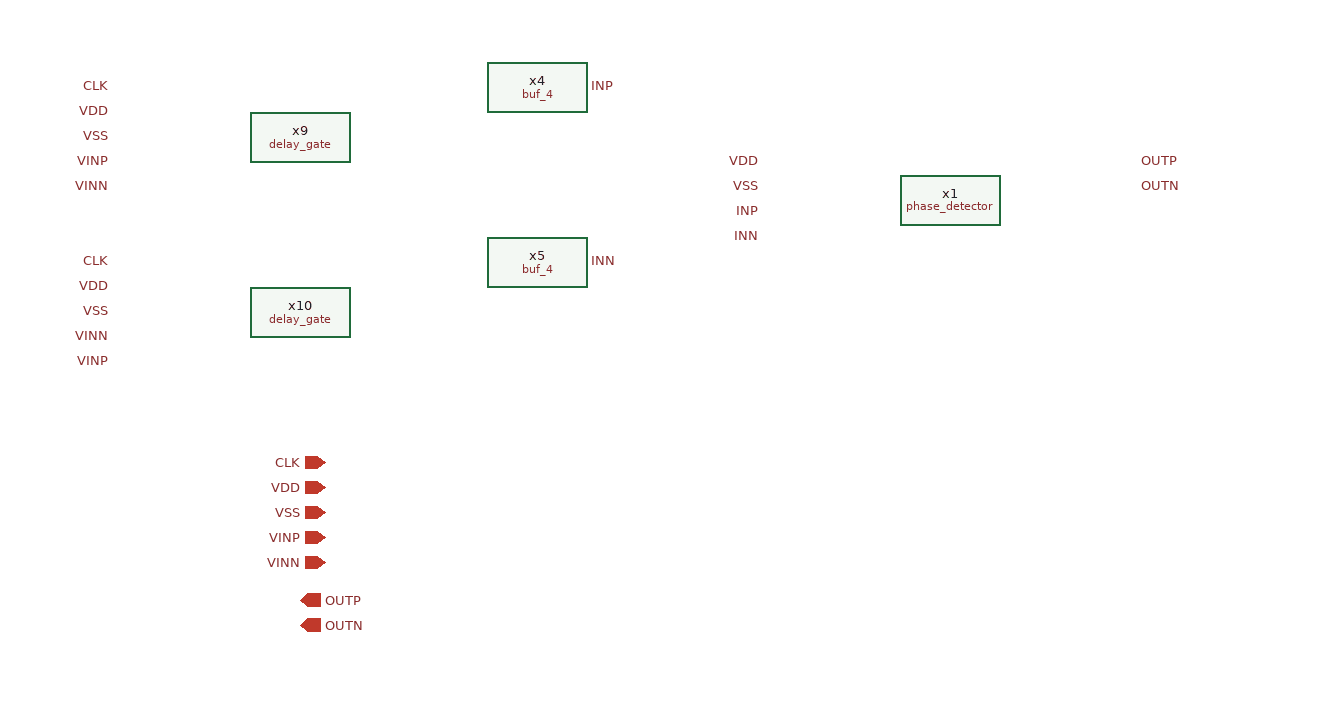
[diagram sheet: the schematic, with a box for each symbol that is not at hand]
v {xschem version=3.4.6 file_version=1.2}
G {}
K {}
V {}
S {}
E {}
C {devices/lab_wire.sym} 1020 -480 0 1 {name=p27 sig_type=std_logic lab=OUTN}
C {devices/lab_wire.sym} 1020 -500 0 1 {name=p28 sig_type=std_logic lab=OUTP}
C {delay_gate.sym} 350 -520 0 0 {name=x9}
C {devices/lab_wire.sym} 580 -560 0 1 {name=p19 sig_type=std_logic lab=INP}
C {delay_gate.sym} 350 -380 0 0 {name=x10}
C {devices/lab_wire.sym} 580 -420 0 1 {name=p20 sig_type=std_logic lab=INN}
C {devices/lab_wire.sym} 200 -540 0 0 {name=p23 sig_type=std_logic lab=VDD}
C {devices/lab_wire.sym} 200 -400 0 0 {name=p24 sig_type=std_logic lab=VDD}
C {devices/lab_wire.sym} 200 -520 0 0 {name=p25 sig_type=std_logic lab=VSS}
C {devices/lab_wire.sym} 200 -380 0 0 {name=p26 sig_type=std_logic lab=VSS}
C {devices/lab_wire.sym} 200 -500 0 0 {name=p29 sig_type=std_logic lab=VINP}
C {devices/lab_wire.sym} 200 -340 0 0 {name=p30 sig_type=std_logic lab=VINP}
C {devices/lab_wire.sym} 200 -360 0 0 {name=p31 sig_type=std_logic lab=VINN}
C {devices/lab_wire.sym} 200 -480 0 0 {name=p32 sig_type=std_logic lab=VINN}
C {devices/lab_wire.sym} 200 -420 0 0 {name=p33 sig_type=std_logic lab=CLK}
C {devices/lab_wire.sym} 200 -560 0 0 {name=p34 sig_type=std_logic lab=CLK}
C {devices/ipin.sym} 370 -240 0 0 {name=p35 sig_type=std_logic lab=VDD}
C {devices/ipin.sym} 370 -220 0 0 {name=p36 sig_type=std_logic lab=VSS}
C {devices/ipin.sym} 370 -200 0 0 {name=p37 sig_type=std_logic lab=VINP}
C {devices/ipin.sym} 370 -180 0 0 {name=p38 sig_type=std_logic lab=VINN}
C {devices/ipin.sym} 370 -260 0 0 {name=p39 sig_type=std_logic lab=CLK}
C {devices/opin.sym} 350 -150 0 0 {name=p40 sig_type=std_logic lab=OUTP}
C {devices/opin.sym} 350 -130 0 0 {name=p41 sig_type=std_logic lab=OUTN}
C {sky130_stdcells/buf_4.sym} 540 -560 0 0 {name=x4 VGND=VSS VNB=VSS VPB=VDD VPWR=VDD prefix=sky130_fd_sc_hd__ }
C {sky130_stdcells/buf_4.sym} 540 -420 0 0 {name=x5 VGND=VSS VNB=VSS VPB=VDD VPWR=VDD prefix=sky130_fd_sc_hd__ }
C {phase_detector.sym} 870 -470 0 0 {name=x1}
C {devices/lab_wire.sym} 720 -500 0 0 {name=p1 sig_type=std_logic lab=VDD}
C {devices/lab_wire.sym} 720 -480 0 0 {name=p2 sig_type=std_logic lab=VSS}
C {devices/lab_wire.sym} 720 -460 0 0 {name=p3 sig_type=std_logic lab=INP}
C {devices/lab_wire.sym} 720 -440 0 0 {name=p4 sig_type=std_logic lab=INN}
